VERSION 5.7 ;
  NOWIREEXTENSIONATPIN ON ;
  DIVIDERCHAR "/" ;
  BUSBITCHARS "[]" ;
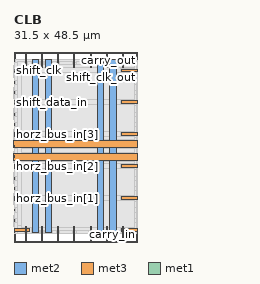
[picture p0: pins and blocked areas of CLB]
MACRO CLB
  CLASS BLOCK ;
  FOREIGN CLB ;
  ORIGIN 0.000 0.000 ;
  SIZE 31.500 BY 48.500 ;
  PIN VGND
    DIRECTION INOUT ;
    USE GROUND ;
    PORT
      LAYER met2 ;
        RECT 8.000 2.480 9.600 46.480 ;
    END
    PORT
      LAYER met2 ;
        RECT 24.500 2.480 26.100 46.480 ;
    END
    PORT
      LAYER met3 ;
        RECT -0.240 24.220 31.520 25.820 ;
    END
    PORT
      LAYER met1 ;
        RECT 0.000 2.480 0.145 2.960 ;
    END
    PORT
      LAYER met1 ;
        RECT 0.000 7.920 0.145 8.400 ;
    END
    PORT
      LAYER met1 ;
        RECT 0.000 13.360 0.145 13.840 ;
    END
    PORT
      LAYER met1 ;
        RECT 0.000 18.800 0.145 19.280 ;
    END
    PORT
      LAYER met1 ;
        RECT 0.000 24.240 0.145 24.720 ;
    END
    PORT
      LAYER met1 ;
        RECT 0.000 29.680 0.145 30.160 ;
    END
    PORT
      LAYER met1 ;
        RECT 0.000 35.120 0.145 35.600 ;
    END
    PORT
      LAYER met1 ;
        RECT 0.000 40.560 0.145 41.040 ;
    END
    PORT
      LAYER met1 ;
        RECT 0.000 46.000 0.145 46.480 ;
    END
  END VGND
  PIN VPWR
    DIRECTION INOUT ;
    USE POWER ;
    PORT
      LAYER met2 ;
        RECT 4.700 2.480 6.300 46.480 ;
    END
    PORT
      LAYER met2 ;
        RECT 21.200 2.480 22.800 46.480 ;
    END
    PORT
      LAYER met3 ;
        RECT -0.240 20.920 31.520 22.520 ;
    END
    PORT
      LAYER met1 ;
        RECT 0.000 5.200 0.145 5.680 ;
    END
    PORT
      LAYER met1 ;
        RECT 0.000 10.640 0.145 11.120 ;
    END
    PORT
      LAYER met1 ;
        RECT 0.000 16.080 0.145 16.560 ;
    END
    PORT
      LAYER met1 ;
        RECT 0.000 21.520 0.145 22.000 ;
    END
    PORT
      LAYER met1 ;
        RECT 0.000 26.960 0.145 27.440 ;
    END
    PORT
      LAYER met1 ;
        RECT 0.000 32.400 0.145 32.880 ;
    END
    PORT
      LAYER met1 ;
        RECT 0.000 37.840 0.145 38.320 ;
    END
    PORT
      LAYER met1 ;
        RECT 0.000 43.280 0.145 43.760 ;
    END
  END VPWR
  PIN carry_in
    DIRECTION INPUT ;
    USE SIGNAL ;
    ANTENNAGATEAREA 0.196500 ;
    PORT
      LAYER met2 ;
        RECT 27.690 0.000 27.970 4.000 ;
    END
  END carry_in
  PIN carry_out
    DIRECTION OUTPUT ;
    USE SIGNAL ;
    ANTENNADIFFAREA 0.445500 ;
    PORT
      LAYER met2 ;
        RECT 27.690 44.500 27.970 48.500 ;
    END
  END carry_out
  PIN clk
    DIRECTION INPUT ;
    USE SIGNAL ;
    ANTENNAGATEAREA 0.852000 ;
    PORT
      LAYER met2 ;
        RECT 19.410 44.500 19.690 48.500 ;
    END
  END clk
  PIN clk_out
    DIRECTION OUTPUT ;
    USE SIGNAL ;
    ANTENNADIFFAREA 0.340600 ;
    PORT
      LAYER met2 ;
        RECT 19.410 0.000 19.690 4.000 ;
    END
  END clk_out
  PIN horz_bus_in[0]
    DIRECTION INPUT ;
    USE SIGNAL ;
    ANTENNAGATEAREA 0.196500 ;
    PORT
      LAYER met3 ;
        RECT 0.000 2.760 4.000 3.360 ;
    END
  END horz_bus_in[0]
  PIN horz_bus_in[1]
    DIRECTION INPUT ;
    USE SIGNAL ;
    ANTENNAGATEAREA 0.196500 ;
    PORT
      LAYER met3 ;
        RECT 0.000 10.920 4.000 11.520 ;
    END
  END horz_bus_in[1]
  PIN horz_bus_in[2]
    DIRECTION INPUT ;
    USE SIGNAL ;
    ANTENNAGATEAREA 0.196500 ;
    PORT
      LAYER met3 ;
        RECT 0.000 19.080 4.000 19.680 ;
    END
  END horz_bus_in[2]
  PIN horz_bus_in[3]
    DIRECTION INPUT ;
    USE SIGNAL ;
    ANTENNAGATEAREA 0.196500 ;
    PORT
      LAYER met3 ;
        RECT 0.000 27.240 4.000 27.840 ;
    END
  END horz_bus_in[3]
  PIN horz_bus_out[0]
    DIRECTION OUTPUT ;
    USE SIGNAL ;
    ANTENNADIFFAREA 0.445500 ;
    PORT
      LAYER met3 ;
        RECT 27.500 2.760 31.500 3.360 ;
    END
  END horz_bus_out[0]
  PIN horz_bus_out[1]
    DIRECTION OUTPUT ;
    USE SIGNAL ;
    ANTENNADIFFAREA 0.445500 ;
    PORT
      LAYER met3 ;
        RECT 27.500 10.920 31.500 11.520 ;
    END
  END horz_bus_out[1]
  PIN horz_bus_out[2]
    DIRECTION OUTPUT ;
    USE SIGNAL ;
    ANTENNADIFFAREA 0.445500 ;
    PORT
      LAYER met3 ;
        RECT 27.500 19.080 31.500 19.680 ;
    END
  END horz_bus_out[2]
  PIN horz_bus_out[3]
    DIRECTION OUTPUT ;
    USE SIGNAL ;
    ANTENNADIFFAREA 0.445500 ;
    PORT
      LAYER met3 ;
        RECT 27.500 27.240 31.500 27.840 ;
    END
  END horz_bus_out[3]
  PIN reset
    DIRECTION INPUT ;
    USE SIGNAL ;
    ANTENNAGATEAREA 0.196500 ;
    PORT
      LAYER met2 ;
        RECT 23.550 44.500 23.830 48.500 ;
    END
  END reset
  PIN reset_out
    DIRECTION OUTPUT ;
    USE SIGNAL ;
    ANTENNADIFFAREA 0.445500 ;
    PORT
      LAYER met2 ;
        RECT 23.550 0.000 23.830 4.000 ;
    END
  END reset_out
  PIN shift_clk
    DIRECTION INPUT ;
    USE SIGNAL ;
    ANTENNAGATEAREA 0.196500 ;
    PORT
      LAYER met3 ;
        RECT 0.000 43.560 4.000 44.160 ;
    END
  END shift_clk
  PIN shift_clk_out
    DIRECTION OUTPUT ;
    USE SIGNAL ;
    ANTENNADIFFAREA 0.445500 ;
    PORT
      LAYER met3 ;
        RECT 27.500 43.560 31.500 44.160 ;
    END
  END shift_clk_out
  PIN shift_data_in
    DIRECTION INPUT ;
    USE SIGNAL ;
    ANTENNAGATEAREA 0.196500 ;
    PORT
      LAYER met3 ;
        RECT 0.000 35.400 4.000 36.000 ;
    END
  END shift_data_in
  PIN shift_data_out
    DIRECTION OUTPUT ;
    USE SIGNAL ;
    ANTENNADIFFAREA 0.445500 ;
    PORT
      LAYER met3 ;
        RECT 27.500 35.400 31.500 36.000 ;
    END
  END shift_data_out
  PIN vert_bus_in[0]
    DIRECTION INPUT ;
    USE SIGNAL ;
    ANTENNAGATEAREA 0.196500 ;
    PORT
      LAYER met2 ;
        RECT 2.850 0.000 3.130 4.000 ;
    END
  END vert_bus_in[0]
  PIN vert_bus_in[1]
    DIRECTION INPUT ;
    USE SIGNAL ;
    ANTENNAGATEAREA 0.196500 ;
    PORT
      LAYER met2 ;
        RECT 6.990 0.000 7.270 4.000 ;
    END
  END vert_bus_in[1]
  PIN vert_bus_in[2]
    DIRECTION INPUT ;
    USE SIGNAL ;
    ANTENNAGATEAREA 0.196500 ;
    PORT
      LAYER met2 ;
        RECT 11.130 0.000 11.410 4.000 ;
    END
  END vert_bus_in[2]
  PIN vert_bus_in[3]
    DIRECTION INPUT ;
    USE SIGNAL ;
    ANTENNAGATEAREA 0.196500 ;
    PORT
      LAYER met2 ;
        RECT 15.270 0.000 15.550 4.000 ;
    END
  END vert_bus_in[3]
  PIN vert_bus_out[0]
    DIRECTION OUTPUT ;
    USE SIGNAL ;
    ANTENNADIFFAREA 0.445500 ;
    PORT
      LAYER met2 ;
        RECT 2.850 44.500 3.130 48.500 ;
    END
  END vert_bus_out[0]
  PIN vert_bus_out[1]
    DIRECTION OUTPUT ;
    USE SIGNAL ;
    ANTENNADIFFAREA 0.445500 ;
    PORT
      LAYER met2 ;
        RECT 6.990 44.500 7.270 48.500 ;
    END
  END vert_bus_out[1]
  PIN vert_bus_out[2]
    DIRECTION OUTPUT ;
    USE SIGNAL ;
    ANTENNADIFFAREA 0.445500 ;
    PORT
      LAYER met2 ;
        RECT 11.130 44.500 11.410 48.500 ;
    END
  END vert_bus_out[2]
  PIN vert_bus_out[3]
    DIRECTION OUTPUT ;
    USE SIGNAL ;
    ANTENNADIFFAREA 0.445500 ;
    PORT
      LAYER met2 ;
        RECT 15.270 44.500 15.550 48.500 ;
    END
  END vert_bus_out[3]
  OBS
      LAYER nwell ;
        RECT 0.000 44.935 31.470 46.325 ;
        RECT -0.190 42.105 31.470 44.935 ;
        RECT 0.000 39.495 31.470 42.105 ;
        RECT -0.190 36.665 31.470 39.495 ;
        RECT 0.000 34.055 31.470 36.665 ;
        RECT -0.190 31.225 31.470 34.055 ;
        RECT 0.000 28.615 31.470 31.225 ;
        RECT -0.190 25.785 31.470 28.615 ;
        RECT 0.000 23.175 31.470 25.785 ;
        RECT -0.190 20.345 31.470 23.175 ;
        RECT 0.000 17.735 31.470 20.345 ;
        RECT -0.190 14.905 31.470 17.735 ;
        RECT 0.000 12.295 31.470 14.905 ;
        RECT -0.190 9.465 31.470 12.295 ;
        RECT 0.000 6.855 31.470 9.465 ;
        RECT -0.190 4.025 31.470 6.855 ;
        RECT 0.000 2.635 31.470 4.025 ;
      LAYER li1 ;
        RECT 0.000 2.635 31.280 46.325 ;
      LAYER met1 ;
        RECT 0.425 45.720 31.280 46.480 ;
        RECT 0.145 44.040 31.280 45.720 ;
        RECT 0.425 43.000 31.280 44.040 ;
        RECT 0.145 41.320 31.280 43.000 ;
        RECT 0.425 40.280 31.280 41.320 ;
        RECT 0.145 38.600 31.280 40.280 ;
        RECT 0.425 37.560 31.280 38.600 ;
        RECT 0.145 35.880 31.280 37.560 ;
        RECT 0.425 34.840 31.280 35.880 ;
        RECT 0.145 33.160 31.280 34.840 ;
        RECT 0.425 32.120 31.280 33.160 ;
        RECT 0.145 30.440 31.280 32.120 ;
        RECT 0.425 29.400 31.280 30.440 ;
        RECT 0.145 27.720 31.280 29.400 ;
        RECT 0.425 26.680 31.280 27.720 ;
        RECT 0.145 25.000 31.280 26.680 ;
        RECT 0.425 23.960 31.280 25.000 ;
        RECT 0.145 22.280 31.280 23.960 ;
        RECT 0.425 21.240 31.280 22.280 ;
        RECT 0.145 19.560 31.280 21.240 ;
        RECT 0.425 18.520 31.280 19.560 ;
        RECT 0.145 16.840 31.280 18.520 ;
        RECT 0.425 15.800 31.280 16.840 ;
        RECT 0.145 14.120 31.280 15.800 ;
        RECT 0.425 13.080 31.280 14.120 ;
        RECT 0.145 11.400 31.280 13.080 ;
        RECT 0.425 10.360 31.280 11.400 ;
        RECT 0.145 8.680 31.280 10.360 ;
        RECT 0.425 7.640 31.280 8.680 ;
        RECT 0.145 5.960 31.280 7.640 ;
        RECT 0.425 4.920 31.280 5.960 ;
        RECT 0.145 3.240 31.280 4.920 ;
        RECT 0.425 2.200 31.280 3.240 ;
        RECT 0.145 2.080 31.280 2.200 ;
      LAYER met2 ;
        RECT 1.020 44.220 2.570 45.970 ;
        RECT 3.410 44.220 4.420 45.970 ;
        RECT 1.020 4.280 4.420 44.220 ;
        RECT 1.020 2.050 2.570 4.280 ;
        RECT 3.410 2.200 4.420 4.280 ;
        RECT 6.580 44.220 6.710 45.970 ;
        RECT 7.550 44.220 7.720 45.970 ;
        RECT 6.580 4.280 7.720 44.220 ;
        RECT 6.580 2.200 6.710 4.280 ;
        RECT 3.410 2.050 6.710 2.200 ;
        RECT 7.550 2.200 7.720 4.280 ;
        RECT 9.880 44.220 10.850 45.970 ;
        RECT 11.690 44.220 14.990 45.970 ;
        RECT 15.830 44.220 19.130 45.970 ;
        RECT 19.970 44.220 20.920 45.970 ;
        RECT 9.880 4.280 20.920 44.220 ;
        RECT 9.880 2.200 10.850 4.280 ;
        RECT 7.550 2.050 10.850 2.200 ;
        RECT 11.690 2.050 14.990 4.280 ;
        RECT 15.830 2.050 19.130 4.280 ;
        RECT 19.970 2.200 20.920 4.280 ;
        RECT 23.080 44.220 23.270 45.970 ;
        RECT 24.110 44.220 24.220 45.970 ;
        RECT 23.080 4.280 24.220 44.220 ;
        RECT 23.080 2.200 23.270 4.280 ;
        RECT 19.970 2.050 23.270 2.200 ;
        RECT 24.110 2.200 24.220 4.280 ;
        RECT 26.380 44.220 27.410 45.970 ;
        RECT 28.250 44.220 30.730 45.970 ;
        RECT 26.380 4.280 30.730 44.220 ;
        RECT 26.380 2.200 27.410 4.280 ;
        RECT 24.110 2.050 27.410 2.200 ;
        RECT 28.250 2.050 30.730 4.280 ;
      LAYER met3 ;
        RECT 1.905 44.560 30.755 45.385 ;
        RECT 4.400 43.160 27.100 44.560 ;
        RECT 1.905 36.400 30.755 43.160 ;
        RECT 4.400 35.000 27.100 36.400 ;
        RECT 1.905 28.240 30.755 35.000 ;
        RECT 4.400 26.840 27.100 28.240 ;
        RECT 1.905 26.220 30.755 26.840 ;
        RECT 1.905 22.920 30.755 23.820 ;
        RECT 1.905 20.080 30.755 20.520 ;
        RECT 4.400 18.680 27.100 20.080 ;
        RECT 1.905 11.920 30.755 18.680 ;
        RECT 4.400 10.520 27.100 11.920 ;
        RECT 1.905 3.760 30.755 10.520 ;
        RECT 4.400 2.895 27.100 3.760 ;
  END
END CLB
END LIBRARY

